VERSION 5.7 ;
  NOWIREEXTENSIONATPIN ON ;
  DIVIDERCHAR "/" ;
  BUSBITCHARS "[]" ;
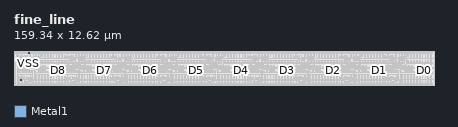
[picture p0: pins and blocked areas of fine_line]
MACRO fine_line
  CLASS BLOCK ;
  FOREIGN fine_line ;
  ORIGIN 0.430 0.430 ;
  SIZE 159.340 BY 12.620 ;
  PIN VSTART
    ANTENNAGATEAREA 0.396000 ;
    PORT
      LAYER Metal1 ;
        RECT 2.000 9.070 2.400 9.410 ;
    END
  END VSTART
  PIN VSTOP
    ANTENNAGATEAREA 0.396000 ;
    PORT
      LAYER Metal1 ;
        RECT 1.900 1.250 2.300 1.570 ;
    END
  END VSTOP
  PIN D8
    ANTENNADIFFAREA 0.897600 ;
    PORT
      LAYER Metal1 ;
        RECT 16.200 4.990 16.600 5.390 ;
    END
  END D8
  PIN D7
    ANTENNADIFFAREA 0.897600 ;
    PORT
      LAYER Metal1 ;
        RECT 33.560 4.990 33.960 5.390 ;
    END
  END D7
  PIN D6
    ANTENNADIFFAREA 0.897600 ;
    PORT
      LAYER Metal1 ;
        RECT 50.920 4.990 51.320 5.390 ;
    END
  END D6
  PIN D5
    ANTENNADIFFAREA 0.897600 ;
    PORT
      LAYER Metal1 ;
        RECT 68.280 4.990 68.680 5.390 ;
    END
  END D5
  PIN D4
    ANTENNADIFFAREA 0.897600 ;
    PORT
      LAYER Metal1 ;
        RECT 85.640 4.990 86.040 5.390 ;
    END
  END D4
  PIN D3
    ANTENNADIFFAREA 0.897600 ;
    PORT
      LAYER Metal1 ;
        RECT 103.000 4.990 103.400 5.390 ;
    END
  END D3
  PIN D2
    ANTENNADIFFAREA 0.897600 ;
    PORT
      LAYER Metal1 ;
        RECT 120.360 4.990 120.760 5.390 ;
    END
  END D2
  PIN D1
    ANTENNADIFFAREA 0.897600 ;
    PORT
      LAYER Metal1 ;
        RECT 137.720 4.990 138.120 5.390 ;
    END
  END D1
  PIN D0
    ANTENNADIFFAREA 0.897600 ;
    PORT
      LAYER Metal1 ;
        RECT 155.080 4.990 155.480 5.390 ;
    END
  END D0
  PIN VDD
    USE POWER ;
    PORT
      LAYER Metal1 ;
        RECT 5.000 11.610 5.400 11.910 ;
    END
  END VDD
  PIN VSS
    USE GROUND ;
    PORT
      LAYER Metal1 ;
        RECT 5.000 7.690 5.400 7.990 ;
    END
  END VSS
  OBS
      LAYER Nwell ;
        RECT -0.430 9.600 158.910 12.190 ;
      LAYER Pwell ;
        RECT -0.430 6.080 158.910 9.600 ;
      LAYER Nwell ;
        RECT -0.430 5.955 5.985 6.080 ;
      LAYER Pwell ;
        RECT 5.985 5.955 7.240 6.080 ;
      LAYER Nwell ;
        RECT 7.240 5.955 23.345 6.080 ;
      LAYER Pwell ;
        RECT 23.345 5.955 24.600 6.080 ;
      LAYER Nwell ;
        RECT 24.600 5.955 40.705 6.080 ;
      LAYER Pwell ;
        RECT 40.705 5.955 41.960 6.080 ;
      LAYER Nwell ;
        RECT 41.960 5.955 58.065 6.080 ;
      LAYER Pwell ;
        RECT 58.065 5.955 59.320 6.080 ;
      LAYER Nwell ;
        RECT 59.320 5.955 75.425 6.080 ;
      LAYER Pwell ;
        RECT 75.425 5.955 76.680 6.080 ;
      LAYER Nwell ;
        RECT 76.680 5.955 92.785 6.080 ;
      LAYER Pwell ;
        RECT 92.785 5.955 94.040 6.080 ;
      LAYER Nwell ;
        RECT 94.040 5.955 110.145 6.080 ;
      LAYER Pwell ;
        RECT 110.145 5.955 111.400 6.080 ;
      LAYER Nwell ;
        RECT 111.400 5.955 127.505 6.080 ;
      LAYER Pwell ;
        RECT 127.505 5.955 128.760 6.080 ;
      LAYER Nwell ;
        RECT 128.760 5.955 144.865 6.080 ;
      LAYER Pwell ;
        RECT 144.865 5.955 146.120 6.080 ;
      LAYER Nwell ;
        RECT 146.120 5.955 158.910 6.080 ;
        RECT -0.430 1.760 158.910 5.955 ;
      LAYER Pwell ;
        RECT -0.430 -0.430 158.910 1.760 ;
      LAYER Metal1 ;
        RECT 0.000 11.910 158.480 12.060 ;
        RECT 0.000 11.610 5.000 11.910 ;
        RECT 5.400 11.610 158.480 11.910 ;
        RECT 0.000 11.460 158.480 11.610 ;
        RECT 0.370 9.760 0.710 11.460 ;
        RECT 1.370 10.245 1.600 10.820 ;
        RECT 2.390 10.475 2.620 11.460 ;
        RECT 3.510 10.480 3.840 10.820 ;
        RECT 1.370 10.015 3.215 10.245 ;
        RECT 0.370 8.140 0.710 9.030 ;
        RECT 1.370 8.400 1.600 10.015 ;
        RECT 3.610 9.670 3.840 10.480 ;
        RECT 4.380 10.135 4.610 10.820 ;
        RECT 5.575 10.500 5.915 11.460 ;
        RECT 6.800 10.420 7.030 11.000 ;
        RECT 7.765 10.650 8.105 11.460 ;
        RECT 8.940 10.420 9.510 11.000 ;
        RECT 10.010 10.445 10.240 11.460 ;
        RECT 6.800 10.190 9.510 10.420 ;
        RECT 4.380 9.900 5.565 10.135 ;
        RECT 5.335 9.865 5.565 9.900 ;
        RECT 3.610 9.440 5.105 9.670 ;
        RECT 5.335 9.525 8.180 9.865 ;
        RECT 1.830 9.410 3.270 9.430 ;
        RECT 1.830 9.070 2.000 9.410 ;
        RECT 2.400 9.070 3.270 9.410 ;
        RECT 1.830 9.050 3.270 9.070 ;
        RECT 2.435 8.140 2.775 8.685 ;
        RECT 3.610 8.400 3.840 9.440 ;
        RECT 5.335 9.210 5.565 9.525 ;
        RECT 8.940 9.245 9.510 10.190 ;
        RECT 11.030 9.770 11.370 11.460 ;
        RECT 12.150 9.770 12.490 11.460 ;
        RECT 13.270 9.770 13.610 11.460 ;
        RECT 14.390 9.770 14.730 11.460 ;
        RECT 15.510 9.770 15.850 11.460 ;
        RECT 16.630 9.770 16.970 11.460 ;
        RECT 17.750 9.770 18.090 11.460 ;
        RECT 18.730 10.245 18.960 10.820 ;
        RECT 19.750 10.475 19.980 11.460 ;
        RECT 20.870 10.480 21.200 10.820 ;
        RECT 18.730 10.015 20.575 10.245 ;
        RECT 4.330 8.975 5.565 9.210 ;
        RECT 6.750 9.010 9.510 9.245 ;
        RECT 4.330 8.400 4.560 8.975 ;
        RECT 5.450 8.140 5.680 8.745 ;
        RECT 6.750 8.440 6.980 9.010 ;
        RECT 7.870 8.140 8.100 8.780 ;
        RECT 8.990 8.440 9.510 9.010 ;
        RECT 10.110 8.140 10.340 8.780 ;
        RECT 11.030 8.140 11.370 9.025 ;
        RECT 12.150 8.140 12.490 9.025 ;
        RECT 13.270 8.140 13.610 9.025 ;
        RECT 14.390 8.140 14.730 9.025 ;
        RECT 15.510 8.140 15.850 9.025 ;
        RECT 16.630 8.140 16.970 9.025 ;
        RECT 17.750 8.140 18.090 9.025 ;
        RECT 18.730 8.400 18.960 10.015 ;
        RECT 20.970 9.670 21.200 10.480 ;
        RECT 21.740 10.135 21.970 10.820 ;
        RECT 22.935 10.500 23.275 11.460 ;
        RECT 24.160 10.420 24.390 11.000 ;
        RECT 25.125 10.650 25.465 11.460 ;
        RECT 26.300 10.420 26.870 11.000 ;
        RECT 27.370 10.445 27.600 11.460 ;
        RECT 24.160 10.190 26.870 10.420 ;
        RECT 21.740 9.900 22.925 10.135 ;
        RECT 22.695 9.865 22.925 9.900 ;
        RECT 20.970 9.440 22.465 9.670 ;
        RECT 22.695 9.525 25.540 9.865 ;
        RECT 19.190 9.050 20.630 9.430 ;
        RECT 19.795 8.140 20.135 8.685 ;
        RECT 20.970 8.400 21.200 9.440 ;
        RECT 22.695 9.210 22.925 9.525 ;
        RECT 26.300 9.245 26.870 10.190 ;
        RECT 28.390 9.770 28.730 11.460 ;
        RECT 29.510 9.770 29.850 11.460 ;
        RECT 30.630 9.770 30.970 11.460 ;
        RECT 31.750 9.770 32.090 11.460 ;
        RECT 32.870 9.770 33.210 11.460 ;
        RECT 33.990 9.770 34.330 11.460 ;
        RECT 35.110 9.770 35.450 11.460 ;
        RECT 36.090 10.245 36.320 10.820 ;
        RECT 37.110 10.475 37.340 11.460 ;
        RECT 38.230 10.480 38.560 10.820 ;
        RECT 36.090 10.015 37.935 10.245 ;
        RECT 21.690 8.975 22.925 9.210 ;
        RECT 24.110 9.010 26.870 9.245 ;
        RECT 21.690 8.400 21.920 8.975 ;
        RECT 22.810 8.140 23.040 8.745 ;
        RECT 24.110 8.440 24.340 9.010 ;
        RECT 25.230 8.140 25.460 8.780 ;
        RECT 26.350 8.440 26.870 9.010 ;
        RECT 27.470 8.140 27.700 8.780 ;
        RECT 28.390 8.140 28.730 9.025 ;
        RECT 29.510 8.140 29.850 9.025 ;
        RECT 30.630 8.140 30.970 9.025 ;
        RECT 31.750 8.140 32.090 9.025 ;
        RECT 32.870 8.140 33.210 9.025 ;
        RECT 33.990 8.140 34.330 9.025 ;
        RECT 35.110 8.140 35.450 9.025 ;
        RECT 36.090 8.400 36.320 10.015 ;
        RECT 38.330 9.670 38.560 10.480 ;
        RECT 39.100 10.135 39.330 10.820 ;
        RECT 40.295 10.500 40.635 11.460 ;
        RECT 41.520 10.420 41.750 11.000 ;
        RECT 42.485 10.650 42.825 11.460 ;
        RECT 43.660 10.420 44.230 11.000 ;
        RECT 44.730 10.445 44.960 11.460 ;
        RECT 41.520 10.190 44.230 10.420 ;
        RECT 39.100 9.900 40.285 10.135 ;
        RECT 40.055 9.865 40.285 9.900 ;
        RECT 38.330 9.440 39.825 9.670 ;
        RECT 40.055 9.525 42.900 9.865 ;
        RECT 36.550 9.050 37.990 9.430 ;
        RECT 37.155 8.140 37.495 8.685 ;
        RECT 38.330 8.400 38.560 9.440 ;
        RECT 40.055 9.210 40.285 9.525 ;
        RECT 43.660 9.245 44.230 10.190 ;
        RECT 45.750 9.770 46.090 11.460 ;
        RECT 46.870 9.770 47.210 11.460 ;
        RECT 47.990 9.770 48.330 11.460 ;
        RECT 49.110 9.770 49.450 11.460 ;
        RECT 50.230 9.770 50.570 11.460 ;
        RECT 51.350 9.770 51.690 11.460 ;
        RECT 52.470 9.770 52.810 11.460 ;
        RECT 53.450 10.245 53.680 10.820 ;
        RECT 54.470 10.475 54.700 11.460 ;
        RECT 55.590 10.480 55.920 10.820 ;
        RECT 53.450 10.015 55.295 10.245 ;
        RECT 39.050 8.975 40.285 9.210 ;
        RECT 41.470 9.010 44.230 9.245 ;
        RECT 39.050 8.400 39.280 8.975 ;
        RECT 40.170 8.140 40.400 8.745 ;
        RECT 41.470 8.440 41.700 9.010 ;
        RECT 42.590 8.140 42.820 8.780 ;
        RECT 43.710 8.440 44.230 9.010 ;
        RECT 44.830 8.140 45.060 8.780 ;
        RECT 45.750 8.140 46.090 9.025 ;
        RECT 46.870 8.140 47.210 9.025 ;
        RECT 47.990 8.140 48.330 9.025 ;
        RECT 49.110 8.140 49.450 9.025 ;
        RECT 50.230 8.140 50.570 9.025 ;
        RECT 51.350 8.140 51.690 9.025 ;
        RECT 52.470 8.140 52.810 9.025 ;
        RECT 53.450 8.400 53.680 10.015 ;
        RECT 55.690 9.670 55.920 10.480 ;
        RECT 56.460 10.135 56.690 10.820 ;
        RECT 57.655 10.500 57.995 11.460 ;
        RECT 58.880 10.420 59.110 11.000 ;
        RECT 59.845 10.650 60.185 11.460 ;
        RECT 61.020 10.420 61.590 11.000 ;
        RECT 62.090 10.445 62.320 11.460 ;
        RECT 58.880 10.190 61.590 10.420 ;
        RECT 56.460 9.900 57.645 10.135 ;
        RECT 57.415 9.865 57.645 9.900 ;
        RECT 55.690 9.440 57.185 9.670 ;
        RECT 57.415 9.525 60.260 9.865 ;
        RECT 53.910 9.050 55.350 9.430 ;
        RECT 54.515 8.140 54.855 8.685 ;
        RECT 55.690 8.400 55.920 9.440 ;
        RECT 57.415 9.210 57.645 9.525 ;
        RECT 61.020 9.245 61.590 10.190 ;
        RECT 63.110 9.770 63.450 11.460 ;
        RECT 64.230 9.770 64.570 11.460 ;
        RECT 65.350 9.770 65.690 11.460 ;
        RECT 66.470 9.770 66.810 11.460 ;
        RECT 67.590 9.770 67.930 11.460 ;
        RECT 68.710 9.770 69.050 11.460 ;
        RECT 69.830 9.770 70.170 11.460 ;
        RECT 70.810 10.245 71.040 10.820 ;
        RECT 71.830 10.475 72.060 11.460 ;
        RECT 72.950 10.480 73.280 10.820 ;
        RECT 70.810 10.015 72.655 10.245 ;
        RECT 56.410 8.975 57.645 9.210 ;
        RECT 58.830 9.010 61.590 9.245 ;
        RECT 56.410 8.400 56.640 8.975 ;
        RECT 57.530 8.140 57.760 8.745 ;
        RECT 58.830 8.440 59.060 9.010 ;
        RECT 59.950 8.140 60.180 8.780 ;
        RECT 61.070 8.440 61.590 9.010 ;
        RECT 62.190 8.140 62.420 8.780 ;
        RECT 63.110 8.140 63.450 9.025 ;
        RECT 64.230 8.140 64.570 9.025 ;
        RECT 65.350 8.140 65.690 9.025 ;
        RECT 66.470 8.140 66.810 9.025 ;
        RECT 67.590 8.140 67.930 9.025 ;
        RECT 68.710 8.140 69.050 9.025 ;
        RECT 69.830 8.140 70.170 9.025 ;
        RECT 70.810 8.400 71.040 10.015 ;
        RECT 73.050 9.670 73.280 10.480 ;
        RECT 73.820 10.135 74.050 10.820 ;
        RECT 75.015 10.500 75.355 11.460 ;
        RECT 76.240 10.420 76.470 11.000 ;
        RECT 77.205 10.650 77.545 11.460 ;
        RECT 78.380 10.420 78.950 11.000 ;
        RECT 79.450 10.445 79.680 11.460 ;
        RECT 76.240 10.190 78.950 10.420 ;
        RECT 73.820 9.900 75.005 10.135 ;
        RECT 74.775 9.865 75.005 9.900 ;
        RECT 73.050 9.440 74.545 9.670 ;
        RECT 74.775 9.525 77.620 9.865 ;
        RECT 71.270 9.050 72.710 9.430 ;
        RECT 71.875 8.140 72.215 8.685 ;
        RECT 73.050 8.400 73.280 9.440 ;
        RECT 74.775 9.210 75.005 9.525 ;
        RECT 78.380 9.245 78.950 10.190 ;
        RECT 80.470 9.770 80.810 11.460 ;
        RECT 81.590 9.770 81.930 11.460 ;
        RECT 82.710 9.770 83.050 11.460 ;
        RECT 83.830 9.770 84.170 11.460 ;
        RECT 84.950 9.770 85.290 11.460 ;
        RECT 86.070 9.770 86.410 11.460 ;
        RECT 87.190 9.770 87.530 11.460 ;
        RECT 88.170 10.245 88.400 10.820 ;
        RECT 89.190 10.475 89.420 11.460 ;
        RECT 90.310 10.480 90.640 10.820 ;
        RECT 88.170 10.015 90.015 10.245 ;
        RECT 73.770 8.975 75.005 9.210 ;
        RECT 76.190 9.010 78.950 9.245 ;
        RECT 73.770 8.400 74.000 8.975 ;
        RECT 74.890 8.140 75.120 8.745 ;
        RECT 76.190 8.440 76.420 9.010 ;
        RECT 77.310 8.140 77.540 8.780 ;
        RECT 78.430 8.440 78.950 9.010 ;
        RECT 79.550 8.140 79.780 8.780 ;
        RECT 80.470 8.140 80.810 9.025 ;
        RECT 81.590 8.140 81.930 9.025 ;
        RECT 82.710 8.140 83.050 9.025 ;
        RECT 83.830 8.140 84.170 9.025 ;
        RECT 84.950 8.140 85.290 9.025 ;
        RECT 86.070 8.140 86.410 9.025 ;
        RECT 87.190 8.140 87.530 9.025 ;
        RECT 88.170 8.400 88.400 10.015 ;
        RECT 90.410 9.670 90.640 10.480 ;
        RECT 91.180 10.135 91.410 10.820 ;
        RECT 92.375 10.500 92.715 11.460 ;
        RECT 93.600 10.420 93.830 11.000 ;
        RECT 94.565 10.650 94.905 11.460 ;
        RECT 95.740 10.420 96.310 11.000 ;
        RECT 96.810 10.445 97.040 11.460 ;
        RECT 93.600 10.190 96.310 10.420 ;
        RECT 91.180 9.900 92.365 10.135 ;
        RECT 92.135 9.865 92.365 9.900 ;
        RECT 90.410 9.440 91.905 9.670 ;
        RECT 92.135 9.525 94.980 9.865 ;
        RECT 88.630 9.050 90.070 9.430 ;
        RECT 89.235 8.140 89.575 8.685 ;
        RECT 90.410 8.400 90.640 9.440 ;
        RECT 92.135 9.210 92.365 9.525 ;
        RECT 95.740 9.245 96.310 10.190 ;
        RECT 97.830 9.770 98.170 11.460 ;
        RECT 98.950 9.770 99.290 11.460 ;
        RECT 100.070 9.770 100.410 11.460 ;
        RECT 101.190 9.770 101.530 11.460 ;
        RECT 102.310 9.770 102.650 11.460 ;
        RECT 103.430 9.770 103.770 11.460 ;
        RECT 104.550 9.770 104.890 11.460 ;
        RECT 105.530 10.245 105.760 10.820 ;
        RECT 106.550 10.475 106.780 11.460 ;
        RECT 107.670 10.480 108.000 10.820 ;
        RECT 105.530 10.015 107.375 10.245 ;
        RECT 91.130 8.975 92.365 9.210 ;
        RECT 93.550 9.010 96.310 9.245 ;
        RECT 91.130 8.400 91.360 8.975 ;
        RECT 92.250 8.140 92.480 8.745 ;
        RECT 93.550 8.440 93.780 9.010 ;
        RECT 94.670 8.140 94.900 8.780 ;
        RECT 95.790 8.440 96.310 9.010 ;
        RECT 96.910 8.140 97.140 8.780 ;
        RECT 97.830 8.140 98.170 9.025 ;
        RECT 98.950 8.140 99.290 9.025 ;
        RECT 100.070 8.140 100.410 9.025 ;
        RECT 101.190 8.140 101.530 9.025 ;
        RECT 102.310 8.140 102.650 9.025 ;
        RECT 103.430 8.140 103.770 9.025 ;
        RECT 104.550 8.140 104.890 9.025 ;
        RECT 105.530 8.400 105.760 10.015 ;
        RECT 107.770 9.670 108.000 10.480 ;
        RECT 108.540 10.135 108.770 10.820 ;
        RECT 109.735 10.500 110.075 11.460 ;
        RECT 110.960 10.420 111.190 11.000 ;
        RECT 111.925 10.650 112.265 11.460 ;
        RECT 113.100 10.420 113.670 11.000 ;
        RECT 114.170 10.445 114.400 11.460 ;
        RECT 110.960 10.190 113.670 10.420 ;
        RECT 108.540 9.900 109.725 10.135 ;
        RECT 109.495 9.865 109.725 9.900 ;
        RECT 107.770 9.440 109.265 9.670 ;
        RECT 109.495 9.525 112.340 9.865 ;
        RECT 105.990 9.050 107.430 9.430 ;
        RECT 106.595 8.140 106.935 8.685 ;
        RECT 107.770 8.400 108.000 9.440 ;
        RECT 109.495 9.210 109.725 9.525 ;
        RECT 113.100 9.245 113.670 10.190 ;
        RECT 115.190 9.770 115.530 11.460 ;
        RECT 116.310 9.770 116.650 11.460 ;
        RECT 117.430 9.770 117.770 11.460 ;
        RECT 118.550 9.770 118.890 11.460 ;
        RECT 119.670 9.770 120.010 11.460 ;
        RECT 120.790 9.770 121.130 11.460 ;
        RECT 121.910 9.770 122.250 11.460 ;
        RECT 122.890 10.245 123.120 10.820 ;
        RECT 123.910 10.475 124.140 11.460 ;
        RECT 125.030 10.480 125.360 10.820 ;
        RECT 122.890 10.015 124.735 10.245 ;
        RECT 108.490 8.975 109.725 9.210 ;
        RECT 110.910 9.010 113.670 9.245 ;
        RECT 108.490 8.400 108.720 8.975 ;
        RECT 109.610 8.140 109.840 8.745 ;
        RECT 110.910 8.440 111.140 9.010 ;
        RECT 112.030 8.140 112.260 8.780 ;
        RECT 113.150 8.440 113.670 9.010 ;
        RECT 114.270 8.140 114.500 8.780 ;
        RECT 115.190 8.140 115.530 9.025 ;
        RECT 116.310 8.140 116.650 9.025 ;
        RECT 117.430 8.140 117.770 9.025 ;
        RECT 118.550 8.140 118.890 9.025 ;
        RECT 119.670 8.140 120.010 9.025 ;
        RECT 120.790 8.140 121.130 9.025 ;
        RECT 121.910 8.140 122.250 9.025 ;
        RECT 122.890 8.400 123.120 10.015 ;
        RECT 125.130 9.670 125.360 10.480 ;
        RECT 125.900 10.135 126.130 10.820 ;
        RECT 127.095 10.500 127.435 11.460 ;
        RECT 128.320 10.420 128.550 11.000 ;
        RECT 129.285 10.650 129.625 11.460 ;
        RECT 130.460 10.420 131.030 11.000 ;
        RECT 131.530 10.445 131.760 11.460 ;
        RECT 128.320 10.190 131.030 10.420 ;
        RECT 125.900 9.900 127.085 10.135 ;
        RECT 126.855 9.865 127.085 9.900 ;
        RECT 125.130 9.440 126.625 9.670 ;
        RECT 126.855 9.525 129.700 9.865 ;
        RECT 123.350 9.050 124.790 9.430 ;
        RECT 123.955 8.140 124.295 8.685 ;
        RECT 125.130 8.400 125.360 9.440 ;
        RECT 126.855 9.210 127.085 9.525 ;
        RECT 130.460 9.245 131.030 10.190 ;
        RECT 132.550 9.770 132.890 11.460 ;
        RECT 133.670 9.770 134.010 11.460 ;
        RECT 134.790 9.770 135.130 11.460 ;
        RECT 135.910 9.770 136.250 11.460 ;
        RECT 137.030 9.770 137.370 11.460 ;
        RECT 138.150 9.770 138.490 11.460 ;
        RECT 139.270 9.770 139.610 11.460 ;
        RECT 140.250 10.245 140.480 10.820 ;
        RECT 141.270 10.475 141.500 11.460 ;
        RECT 142.390 10.480 142.720 10.820 ;
        RECT 140.250 10.015 142.095 10.245 ;
        RECT 125.850 8.975 127.085 9.210 ;
        RECT 128.270 9.010 131.030 9.245 ;
        RECT 125.850 8.400 126.080 8.975 ;
        RECT 126.970 8.140 127.200 8.745 ;
        RECT 128.270 8.440 128.500 9.010 ;
        RECT 129.390 8.140 129.620 8.780 ;
        RECT 130.510 8.440 131.030 9.010 ;
        RECT 131.630 8.140 131.860 8.780 ;
        RECT 132.550 8.140 132.890 9.025 ;
        RECT 133.670 8.140 134.010 9.025 ;
        RECT 134.790 8.140 135.130 9.025 ;
        RECT 135.910 8.140 136.250 9.025 ;
        RECT 137.030 8.140 137.370 9.025 ;
        RECT 138.150 8.140 138.490 9.025 ;
        RECT 139.270 8.140 139.610 9.025 ;
        RECT 140.250 8.400 140.480 10.015 ;
        RECT 142.490 9.670 142.720 10.480 ;
        RECT 143.260 10.135 143.490 10.820 ;
        RECT 144.455 10.500 144.795 11.460 ;
        RECT 145.680 10.420 145.910 11.000 ;
        RECT 146.645 10.650 146.985 11.460 ;
        RECT 147.820 10.420 148.390 11.000 ;
        RECT 148.890 10.445 149.120 11.460 ;
        RECT 145.680 10.190 148.390 10.420 ;
        RECT 143.260 9.900 144.445 10.135 ;
        RECT 144.215 9.865 144.445 9.900 ;
        RECT 142.490 9.440 143.985 9.670 ;
        RECT 144.215 9.525 147.060 9.865 ;
        RECT 140.710 9.050 142.150 9.430 ;
        RECT 141.315 8.140 141.655 8.685 ;
        RECT 142.490 8.400 142.720 9.440 ;
        RECT 144.215 9.210 144.445 9.525 ;
        RECT 147.820 9.245 148.390 10.190 ;
        RECT 149.910 9.770 150.250 11.460 ;
        RECT 151.030 9.770 151.370 11.460 ;
        RECT 152.150 9.770 152.490 11.460 ;
        RECT 153.270 9.770 153.610 11.460 ;
        RECT 154.390 9.770 154.730 11.460 ;
        RECT 155.510 9.770 155.850 11.460 ;
        RECT 156.630 9.770 156.970 11.460 ;
        RECT 157.730 9.760 158.070 11.460 ;
        RECT 143.210 8.975 144.445 9.210 ;
        RECT 145.630 9.010 148.390 9.245 ;
        RECT 143.210 8.400 143.440 8.975 ;
        RECT 144.330 8.140 144.560 8.745 ;
        RECT 145.630 8.440 145.860 9.010 ;
        RECT 146.750 8.140 146.980 8.780 ;
        RECT 147.870 8.440 148.390 9.010 ;
        RECT 148.990 8.140 149.220 8.780 ;
        RECT 149.910 8.140 150.250 9.025 ;
        RECT 151.030 8.140 151.370 9.025 ;
        RECT 152.150 8.140 152.490 9.025 ;
        RECT 153.270 8.140 153.610 9.025 ;
        RECT 154.390 8.140 154.730 9.025 ;
        RECT 155.510 8.140 155.850 9.025 ;
        RECT 156.630 8.140 156.970 9.025 ;
        RECT 157.730 8.140 158.070 9.030 ;
        RECT 0.000 7.990 158.480 8.140 ;
        RECT 0.000 7.690 5.000 7.990 ;
        RECT 5.400 7.690 158.480 7.990 ;
        RECT 0.000 7.540 158.480 7.690 ;
        RECT 0.370 6.650 0.710 7.540 ;
        RECT 1.365 6.560 1.595 7.030 ;
        RECT 2.430 6.790 2.770 7.540 ;
        RECT 1.365 6.330 3.265 6.560 ;
        RECT 0.370 4.220 0.710 5.920 ;
        RECT 1.770 5.690 2.710 6.070 ;
        RECT 3.035 5.370 3.265 6.330 ;
        RECT 3.605 6.515 3.835 7.030 ;
        RECT 4.270 6.750 4.610 7.540 ;
        RECT 4.965 7.080 7.515 7.310 ;
        RECT 8.910 7.255 9.250 7.540 ;
        RECT 4.965 6.515 5.195 7.080 ;
        RECT 3.605 6.285 5.195 6.515 ;
        RECT 4.965 5.750 5.195 6.285 ;
        RECT 1.465 5.140 3.265 5.370 ;
        RECT 1.465 4.685 1.695 5.140 ;
        RECT 2.430 4.220 2.770 4.910 ;
        RECT 3.035 4.860 3.265 5.140 ;
        RECT 3.505 5.515 5.195 5.750 ;
        RECT 3.505 5.130 3.735 5.515 ;
        RECT 3.965 4.955 5.240 5.190 ;
        RECT 5.690 5.130 6.095 6.630 ;
        RECT 6.445 5.600 6.790 6.850 ;
        RECT 7.285 6.060 7.515 7.080 ;
        RECT 10.250 6.520 10.590 6.980 ;
        RECT 8.250 6.290 10.590 6.520 ;
        RECT 7.285 5.830 9.990 6.060 ;
        RECT 6.445 5.370 9.530 5.600 ;
        RECT 3.965 4.860 4.195 4.955 ;
        RECT 3.035 4.625 4.195 4.860 ;
        RECT 5.010 4.680 5.240 4.955 ;
        RECT 6.730 4.910 7.070 5.370 ;
        RECT 4.425 4.220 4.655 4.655 ;
        RECT 5.010 4.450 7.710 4.680 ;
        RECT 8.750 4.220 9.090 5.140 ;
        RECT 9.760 4.680 9.990 5.830 ;
        RECT 10.245 4.910 10.590 6.290 ;
        RECT 10.840 4.680 11.070 6.615 ;
        RECT 11.370 5.945 11.710 6.980 ;
        RECT 13.605 6.735 13.835 7.540 ;
        RECT 14.725 6.440 14.990 7.085 ;
        RECT 15.545 6.950 15.775 7.540 ;
        RECT 12.890 6.340 14.990 6.440 ;
        RECT 12.890 6.210 16.215 6.340 ;
        RECT 14.765 6.000 16.215 6.210 ;
        RECT 11.370 5.710 14.470 5.945 ;
        RECT 11.370 4.910 11.710 5.710 ;
        RECT 9.760 4.450 12.450 4.680 ;
        RECT 13.745 4.220 13.975 5.205 ;
        RECT 14.765 4.810 14.995 6.000 ;
        RECT 16.590 5.510 16.970 7.290 ;
        RECT 17.750 6.655 18.090 7.540 ;
        RECT 18.725 6.560 18.955 7.030 ;
        RECT 19.790 6.790 20.130 7.540 ;
        RECT 18.725 6.330 20.625 6.560 ;
        RECT 15.955 5.390 16.970 5.510 ;
        RECT 15.485 4.220 15.715 5.205 ;
        RECT 15.955 4.990 16.200 5.390 ;
        RECT 16.600 4.990 16.970 5.390 ;
        RECT 15.955 4.865 16.970 4.990 ;
        RECT 17.750 4.220 18.090 5.910 ;
        RECT 19.130 5.690 20.070 6.070 ;
        RECT 20.395 5.370 20.625 6.330 ;
        RECT 20.965 6.515 21.195 7.030 ;
        RECT 21.630 6.750 21.970 7.540 ;
        RECT 22.325 7.080 24.875 7.310 ;
        RECT 26.270 7.255 26.610 7.540 ;
        RECT 22.325 6.515 22.555 7.080 ;
        RECT 20.965 6.285 22.555 6.515 ;
        RECT 22.325 5.750 22.555 6.285 ;
        RECT 18.825 5.140 20.625 5.370 ;
        RECT 18.825 4.685 19.055 5.140 ;
        RECT 19.790 4.220 20.130 4.910 ;
        RECT 20.395 4.860 20.625 5.140 ;
        RECT 20.865 5.515 22.555 5.750 ;
        RECT 20.865 5.130 21.095 5.515 ;
        RECT 21.325 4.955 22.600 5.190 ;
        RECT 23.050 5.130 23.455 6.630 ;
        RECT 23.805 5.600 24.150 6.850 ;
        RECT 24.645 6.060 24.875 7.080 ;
        RECT 27.610 6.520 27.950 6.980 ;
        RECT 25.610 6.290 27.950 6.520 ;
        RECT 24.645 5.830 27.350 6.060 ;
        RECT 23.805 5.370 26.890 5.600 ;
        RECT 21.325 4.860 21.555 4.955 ;
        RECT 20.395 4.625 21.555 4.860 ;
        RECT 22.370 4.680 22.600 4.955 ;
        RECT 24.090 4.910 24.430 5.370 ;
        RECT 21.785 4.220 22.015 4.655 ;
        RECT 22.370 4.450 25.070 4.680 ;
        RECT 26.110 4.220 26.450 5.140 ;
        RECT 27.120 4.680 27.350 5.830 ;
        RECT 27.605 4.910 27.950 6.290 ;
        RECT 28.200 4.680 28.430 6.615 ;
        RECT 28.730 5.945 29.070 6.980 ;
        RECT 30.965 6.735 31.195 7.540 ;
        RECT 32.085 6.440 32.350 7.085 ;
        RECT 32.905 6.950 33.135 7.540 ;
        RECT 30.250 6.340 32.350 6.440 ;
        RECT 30.250 6.210 33.575 6.340 ;
        RECT 32.125 6.000 33.575 6.210 ;
        RECT 28.730 5.710 31.830 5.945 ;
        RECT 28.730 4.910 29.070 5.710 ;
        RECT 27.120 4.450 29.810 4.680 ;
        RECT 31.105 4.220 31.335 5.205 ;
        RECT 32.125 4.810 32.355 6.000 ;
        RECT 33.950 5.510 34.330 7.290 ;
        RECT 35.110 6.655 35.450 7.540 ;
        RECT 36.085 6.560 36.315 7.030 ;
        RECT 37.150 6.790 37.490 7.540 ;
        RECT 36.085 6.330 37.985 6.560 ;
        RECT 33.315 5.390 34.330 5.510 ;
        RECT 32.845 4.220 33.075 5.205 ;
        RECT 33.315 4.990 33.560 5.390 ;
        RECT 33.960 4.990 34.330 5.390 ;
        RECT 33.315 4.865 34.330 4.990 ;
        RECT 35.110 4.220 35.450 5.910 ;
        RECT 36.490 5.690 37.430 6.070 ;
        RECT 37.755 5.370 37.985 6.330 ;
        RECT 38.325 6.515 38.555 7.030 ;
        RECT 38.990 6.750 39.330 7.540 ;
        RECT 39.685 7.080 42.235 7.310 ;
        RECT 43.630 7.255 43.970 7.540 ;
        RECT 39.685 6.515 39.915 7.080 ;
        RECT 38.325 6.285 39.915 6.515 ;
        RECT 39.685 5.750 39.915 6.285 ;
        RECT 36.185 5.140 37.985 5.370 ;
        RECT 36.185 4.685 36.415 5.140 ;
        RECT 37.150 4.220 37.490 4.910 ;
        RECT 37.755 4.860 37.985 5.140 ;
        RECT 38.225 5.515 39.915 5.750 ;
        RECT 38.225 5.130 38.455 5.515 ;
        RECT 38.685 4.955 39.960 5.190 ;
        RECT 40.410 5.130 40.815 6.630 ;
        RECT 41.165 5.600 41.510 6.850 ;
        RECT 42.005 6.060 42.235 7.080 ;
        RECT 44.970 6.520 45.310 6.980 ;
        RECT 42.970 6.290 45.310 6.520 ;
        RECT 42.005 5.830 44.710 6.060 ;
        RECT 41.165 5.370 44.250 5.600 ;
        RECT 38.685 4.860 38.915 4.955 ;
        RECT 37.755 4.625 38.915 4.860 ;
        RECT 39.730 4.680 39.960 4.955 ;
        RECT 41.450 4.910 41.790 5.370 ;
        RECT 39.145 4.220 39.375 4.655 ;
        RECT 39.730 4.450 42.430 4.680 ;
        RECT 43.470 4.220 43.810 5.140 ;
        RECT 44.480 4.680 44.710 5.830 ;
        RECT 44.965 4.910 45.310 6.290 ;
        RECT 45.560 4.680 45.790 6.615 ;
        RECT 46.090 5.945 46.430 6.980 ;
        RECT 48.325 6.735 48.555 7.540 ;
        RECT 49.445 6.440 49.710 7.085 ;
        RECT 50.265 6.950 50.495 7.540 ;
        RECT 47.610 6.340 49.710 6.440 ;
        RECT 47.610 6.210 50.935 6.340 ;
        RECT 49.485 6.000 50.935 6.210 ;
        RECT 46.090 5.710 49.190 5.945 ;
        RECT 46.090 4.910 46.430 5.710 ;
        RECT 44.480 4.450 47.170 4.680 ;
        RECT 48.465 4.220 48.695 5.205 ;
        RECT 49.485 4.810 49.715 6.000 ;
        RECT 51.310 5.510 51.690 7.290 ;
        RECT 52.470 6.655 52.810 7.540 ;
        RECT 53.445 6.560 53.675 7.030 ;
        RECT 54.510 6.790 54.850 7.540 ;
        RECT 53.445 6.330 55.345 6.560 ;
        RECT 50.675 5.390 51.690 5.510 ;
        RECT 50.205 4.220 50.435 5.205 ;
        RECT 50.675 4.990 50.920 5.390 ;
        RECT 51.320 4.990 51.690 5.390 ;
        RECT 50.675 4.865 51.690 4.990 ;
        RECT 52.470 4.220 52.810 5.910 ;
        RECT 53.850 5.690 54.790 6.070 ;
        RECT 55.115 5.370 55.345 6.330 ;
        RECT 55.685 6.515 55.915 7.030 ;
        RECT 56.350 6.750 56.690 7.540 ;
        RECT 57.045 7.080 59.595 7.310 ;
        RECT 60.990 7.255 61.330 7.540 ;
        RECT 57.045 6.515 57.275 7.080 ;
        RECT 55.685 6.285 57.275 6.515 ;
        RECT 57.045 5.750 57.275 6.285 ;
        RECT 53.545 5.140 55.345 5.370 ;
        RECT 53.545 4.685 53.775 5.140 ;
        RECT 54.510 4.220 54.850 4.910 ;
        RECT 55.115 4.860 55.345 5.140 ;
        RECT 55.585 5.515 57.275 5.750 ;
        RECT 55.585 5.130 55.815 5.515 ;
        RECT 56.045 4.955 57.320 5.190 ;
        RECT 57.770 5.130 58.175 6.630 ;
        RECT 58.525 5.600 58.870 6.850 ;
        RECT 59.365 6.060 59.595 7.080 ;
        RECT 62.330 6.520 62.670 6.980 ;
        RECT 60.330 6.290 62.670 6.520 ;
        RECT 59.365 5.830 62.070 6.060 ;
        RECT 58.525 5.370 61.610 5.600 ;
        RECT 56.045 4.860 56.275 4.955 ;
        RECT 55.115 4.625 56.275 4.860 ;
        RECT 57.090 4.680 57.320 4.955 ;
        RECT 58.810 4.910 59.150 5.370 ;
        RECT 56.505 4.220 56.735 4.655 ;
        RECT 57.090 4.450 59.790 4.680 ;
        RECT 60.830 4.220 61.170 5.140 ;
        RECT 61.840 4.680 62.070 5.830 ;
        RECT 62.325 4.910 62.670 6.290 ;
        RECT 62.920 4.680 63.150 6.615 ;
        RECT 63.450 5.945 63.790 6.980 ;
        RECT 65.685 6.735 65.915 7.540 ;
        RECT 66.805 6.440 67.070 7.085 ;
        RECT 67.625 6.950 67.855 7.540 ;
        RECT 64.970 6.340 67.070 6.440 ;
        RECT 64.970 6.210 68.295 6.340 ;
        RECT 66.845 6.000 68.295 6.210 ;
        RECT 63.450 5.710 66.550 5.945 ;
        RECT 63.450 4.910 63.790 5.710 ;
        RECT 61.840 4.450 64.530 4.680 ;
        RECT 65.825 4.220 66.055 5.205 ;
        RECT 66.845 4.810 67.075 6.000 ;
        RECT 68.670 5.510 69.050 7.290 ;
        RECT 69.830 6.655 70.170 7.540 ;
        RECT 70.805 6.560 71.035 7.030 ;
        RECT 71.870 6.790 72.210 7.540 ;
        RECT 70.805 6.330 72.705 6.560 ;
        RECT 68.035 5.390 69.050 5.510 ;
        RECT 67.565 4.220 67.795 5.205 ;
        RECT 68.035 4.990 68.280 5.390 ;
        RECT 68.680 4.990 69.050 5.390 ;
        RECT 68.035 4.865 69.050 4.990 ;
        RECT 69.830 4.220 70.170 5.910 ;
        RECT 71.210 5.690 72.150 6.070 ;
        RECT 72.475 5.370 72.705 6.330 ;
        RECT 73.045 6.515 73.275 7.030 ;
        RECT 73.710 6.750 74.050 7.540 ;
        RECT 74.405 7.080 76.955 7.310 ;
        RECT 78.350 7.255 78.690 7.540 ;
        RECT 74.405 6.515 74.635 7.080 ;
        RECT 73.045 6.285 74.635 6.515 ;
        RECT 74.405 5.750 74.635 6.285 ;
        RECT 70.905 5.140 72.705 5.370 ;
        RECT 70.905 4.685 71.135 5.140 ;
        RECT 71.870 4.220 72.210 4.910 ;
        RECT 72.475 4.860 72.705 5.140 ;
        RECT 72.945 5.515 74.635 5.750 ;
        RECT 72.945 5.130 73.175 5.515 ;
        RECT 73.405 4.955 74.680 5.190 ;
        RECT 75.130 5.130 75.535 6.630 ;
        RECT 75.885 5.600 76.230 6.850 ;
        RECT 76.725 6.060 76.955 7.080 ;
        RECT 79.690 6.520 80.030 6.980 ;
        RECT 77.690 6.290 80.030 6.520 ;
        RECT 76.725 5.830 79.430 6.060 ;
        RECT 75.885 5.370 78.970 5.600 ;
        RECT 73.405 4.860 73.635 4.955 ;
        RECT 72.475 4.625 73.635 4.860 ;
        RECT 74.450 4.680 74.680 4.955 ;
        RECT 76.170 4.910 76.510 5.370 ;
        RECT 73.865 4.220 74.095 4.655 ;
        RECT 74.450 4.450 77.150 4.680 ;
        RECT 78.190 4.220 78.530 5.140 ;
        RECT 79.200 4.680 79.430 5.830 ;
        RECT 79.685 4.910 80.030 6.290 ;
        RECT 80.280 4.680 80.510 6.615 ;
        RECT 80.810 5.945 81.150 6.980 ;
        RECT 83.045 6.735 83.275 7.540 ;
        RECT 84.165 6.440 84.430 7.085 ;
        RECT 84.985 6.950 85.215 7.540 ;
        RECT 82.330 6.340 84.430 6.440 ;
        RECT 82.330 6.210 85.655 6.340 ;
        RECT 84.205 6.000 85.655 6.210 ;
        RECT 80.810 5.710 83.910 5.945 ;
        RECT 80.810 4.910 81.150 5.710 ;
        RECT 79.200 4.450 81.890 4.680 ;
        RECT 83.185 4.220 83.415 5.205 ;
        RECT 84.205 4.810 84.435 6.000 ;
        RECT 86.030 5.510 86.410 7.290 ;
        RECT 87.190 6.655 87.530 7.540 ;
        RECT 88.165 6.560 88.395 7.030 ;
        RECT 89.230 6.790 89.570 7.540 ;
        RECT 88.165 6.330 90.065 6.560 ;
        RECT 85.395 5.390 86.410 5.510 ;
        RECT 84.925 4.220 85.155 5.205 ;
        RECT 85.395 4.990 85.640 5.390 ;
        RECT 86.040 4.990 86.410 5.390 ;
        RECT 85.395 4.865 86.410 4.990 ;
        RECT 87.190 4.220 87.530 5.910 ;
        RECT 88.570 5.690 89.510 6.070 ;
        RECT 89.835 5.370 90.065 6.330 ;
        RECT 90.405 6.515 90.635 7.030 ;
        RECT 91.070 6.750 91.410 7.540 ;
        RECT 91.765 7.080 94.315 7.310 ;
        RECT 95.710 7.255 96.050 7.540 ;
        RECT 91.765 6.515 91.995 7.080 ;
        RECT 90.405 6.285 91.995 6.515 ;
        RECT 91.765 5.750 91.995 6.285 ;
        RECT 88.265 5.140 90.065 5.370 ;
        RECT 88.265 4.685 88.495 5.140 ;
        RECT 89.230 4.220 89.570 4.910 ;
        RECT 89.835 4.860 90.065 5.140 ;
        RECT 90.305 5.515 91.995 5.750 ;
        RECT 90.305 5.130 90.535 5.515 ;
        RECT 90.765 4.955 92.040 5.190 ;
        RECT 92.490 5.130 92.895 6.630 ;
        RECT 93.245 5.600 93.590 6.850 ;
        RECT 94.085 6.060 94.315 7.080 ;
        RECT 97.050 6.520 97.390 6.980 ;
        RECT 95.050 6.290 97.390 6.520 ;
        RECT 94.085 5.830 96.790 6.060 ;
        RECT 93.245 5.370 96.330 5.600 ;
        RECT 90.765 4.860 90.995 4.955 ;
        RECT 89.835 4.625 90.995 4.860 ;
        RECT 91.810 4.680 92.040 4.955 ;
        RECT 93.530 4.910 93.870 5.370 ;
        RECT 91.225 4.220 91.455 4.655 ;
        RECT 91.810 4.450 94.510 4.680 ;
        RECT 95.550 4.220 95.890 5.140 ;
        RECT 96.560 4.680 96.790 5.830 ;
        RECT 97.045 4.910 97.390 6.290 ;
        RECT 97.640 4.680 97.870 6.615 ;
        RECT 98.170 5.945 98.510 6.980 ;
        RECT 100.405 6.735 100.635 7.540 ;
        RECT 101.525 6.440 101.790 7.085 ;
        RECT 102.345 6.950 102.575 7.540 ;
        RECT 99.690 6.340 101.790 6.440 ;
        RECT 99.690 6.210 103.015 6.340 ;
        RECT 101.565 6.000 103.015 6.210 ;
        RECT 98.170 5.710 101.270 5.945 ;
        RECT 98.170 4.910 98.510 5.710 ;
        RECT 96.560 4.450 99.250 4.680 ;
        RECT 100.545 4.220 100.775 5.205 ;
        RECT 101.565 4.810 101.795 6.000 ;
        RECT 103.390 5.510 103.770 7.290 ;
        RECT 104.550 6.655 104.890 7.540 ;
        RECT 105.525 6.560 105.755 7.030 ;
        RECT 106.590 6.790 106.930 7.540 ;
        RECT 105.525 6.330 107.425 6.560 ;
        RECT 102.755 5.390 103.770 5.510 ;
        RECT 102.285 4.220 102.515 5.205 ;
        RECT 102.755 4.990 103.000 5.390 ;
        RECT 103.400 4.990 103.770 5.390 ;
        RECT 102.755 4.865 103.770 4.990 ;
        RECT 104.550 4.220 104.890 5.910 ;
        RECT 105.930 5.690 106.870 6.070 ;
        RECT 107.195 5.370 107.425 6.330 ;
        RECT 107.765 6.515 107.995 7.030 ;
        RECT 108.430 6.750 108.770 7.540 ;
        RECT 109.125 7.080 111.675 7.310 ;
        RECT 113.070 7.255 113.410 7.540 ;
        RECT 109.125 6.515 109.355 7.080 ;
        RECT 107.765 6.285 109.355 6.515 ;
        RECT 109.125 5.750 109.355 6.285 ;
        RECT 105.625 5.140 107.425 5.370 ;
        RECT 105.625 4.685 105.855 5.140 ;
        RECT 106.590 4.220 106.930 4.910 ;
        RECT 107.195 4.860 107.425 5.140 ;
        RECT 107.665 5.515 109.355 5.750 ;
        RECT 107.665 5.130 107.895 5.515 ;
        RECT 108.125 4.955 109.400 5.190 ;
        RECT 109.850 5.130 110.255 6.630 ;
        RECT 110.605 5.600 110.950 6.850 ;
        RECT 111.445 6.060 111.675 7.080 ;
        RECT 114.410 6.520 114.750 6.980 ;
        RECT 112.410 6.290 114.750 6.520 ;
        RECT 111.445 5.830 114.150 6.060 ;
        RECT 110.605 5.370 113.690 5.600 ;
        RECT 108.125 4.860 108.355 4.955 ;
        RECT 107.195 4.625 108.355 4.860 ;
        RECT 109.170 4.680 109.400 4.955 ;
        RECT 110.890 4.910 111.230 5.370 ;
        RECT 108.585 4.220 108.815 4.655 ;
        RECT 109.170 4.450 111.870 4.680 ;
        RECT 112.910 4.220 113.250 5.140 ;
        RECT 113.920 4.680 114.150 5.830 ;
        RECT 114.405 4.910 114.750 6.290 ;
        RECT 115.000 4.680 115.230 6.615 ;
        RECT 115.530 5.945 115.870 6.980 ;
        RECT 117.765 6.735 117.995 7.540 ;
        RECT 118.885 6.440 119.150 7.085 ;
        RECT 119.705 6.950 119.935 7.540 ;
        RECT 117.050 6.340 119.150 6.440 ;
        RECT 117.050 6.210 120.375 6.340 ;
        RECT 118.925 6.000 120.375 6.210 ;
        RECT 115.530 5.710 118.630 5.945 ;
        RECT 115.530 4.910 115.870 5.710 ;
        RECT 113.920 4.450 116.610 4.680 ;
        RECT 117.905 4.220 118.135 5.205 ;
        RECT 118.925 4.810 119.155 6.000 ;
        RECT 120.750 5.510 121.130 7.290 ;
        RECT 121.910 6.655 122.250 7.540 ;
        RECT 122.885 6.560 123.115 7.030 ;
        RECT 123.950 6.790 124.290 7.540 ;
        RECT 122.885 6.330 124.785 6.560 ;
        RECT 120.115 5.390 121.130 5.510 ;
        RECT 119.645 4.220 119.875 5.205 ;
        RECT 120.115 4.990 120.360 5.390 ;
        RECT 120.760 4.990 121.130 5.390 ;
        RECT 120.115 4.865 121.130 4.990 ;
        RECT 121.910 4.220 122.250 5.910 ;
        RECT 123.290 5.690 124.230 6.070 ;
        RECT 124.555 5.370 124.785 6.330 ;
        RECT 125.125 6.515 125.355 7.030 ;
        RECT 125.790 6.750 126.130 7.540 ;
        RECT 126.485 7.080 129.035 7.310 ;
        RECT 130.430 7.255 130.770 7.540 ;
        RECT 126.485 6.515 126.715 7.080 ;
        RECT 125.125 6.285 126.715 6.515 ;
        RECT 126.485 5.750 126.715 6.285 ;
        RECT 122.985 5.140 124.785 5.370 ;
        RECT 122.985 4.685 123.215 5.140 ;
        RECT 123.950 4.220 124.290 4.910 ;
        RECT 124.555 4.860 124.785 5.140 ;
        RECT 125.025 5.515 126.715 5.750 ;
        RECT 125.025 5.130 125.255 5.515 ;
        RECT 125.485 4.955 126.760 5.190 ;
        RECT 127.210 5.130 127.615 6.630 ;
        RECT 127.965 5.600 128.310 6.850 ;
        RECT 128.805 6.060 129.035 7.080 ;
        RECT 131.770 6.520 132.110 6.980 ;
        RECT 129.770 6.290 132.110 6.520 ;
        RECT 128.805 5.830 131.510 6.060 ;
        RECT 127.965 5.370 131.050 5.600 ;
        RECT 125.485 4.860 125.715 4.955 ;
        RECT 124.555 4.625 125.715 4.860 ;
        RECT 126.530 4.680 126.760 4.955 ;
        RECT 128.250 4.910 128.590 5.370 ;
        RECT 125.945 4.220 126.175 4.655 ;
        RECT 126.530 4.450 129.230 4.680 ;
        RECT 130.270 4.220 130.610 5.140 ;
        RECT 131.280 4.680 131.510 5.830 ;
        RECT 131.765 4.910 132.110 6.290 ;
        RECT 132.360 4.680 132.590 6.615 ;
        RECT 132.890 5.945 133.230 6.980 ;
        RECT 135.125 6.735 135.355 7.540 ;
        RECT 136.245 6.440 136.510 7.085 ;
        RECT 137.065 6.950 137.295 7.540 ;
        RECT 134.410 6.340 136.510 6.440 ;
        RECT 134.410 6.210 137.735 6.340 ;
        RECT 136.285 6.000 137.735 6.210 ;
        RECT 132.890 5.710 135.990 5.945 ;
        RECT 132.890 4.910 133.230 5.710 ;
        RECT 131.280 4.450 133.970 4.680 ;
        RECT 135.265 4.220 135.495 5.205 ;
        RECT 136.285 4.810 136.515 6.000 ;
        RECT 138.110 5.510 138.490 7.290 ;
        RECT 139.270 6.655 139.610 7.540 ;
        RECT 140.245 6.560 140.475 7.030 ;
        RECT 141.310 6.790 141.650 7.540 ;
        RECT 140.245 6.330 142.145 6.560 ;
        RECT 137.475 5.390 138.490 5.510 ;
        RECT 137.005 4.220 137.235 5.205 ;
        RECT 137.475 4.990 137.720 5.390 ;
        RECT 138.120 4.990 138.490 5.390 ;
        RECT 137.475 4.865 138.490 4.990 ;
        RECT 139.270 4.220 139.610 5.910 ;
        RECT 140.650 5.690 141.590 6.070 ;
        RECT 141.915 5.370 142.145 6.330 ;
        RECT 142.485 6.515 142.715 7.030 ;
        RECT 143.150 6.750 143.490 7.540 ;
        RECT 143.845 7.080 146.395 7.310 ;
        RECT 147.790 7.255 148.130 7.540 ;
        RECT 143.845 6.515 144.075 7.080 ;
        RECT 142.485 6.285 144.075 6.515 ;
        RECT 143.845 5.750 144.075 6.285 ;
        RECT 140.345 5.140 142.145 5.370 ;
        RECT 140.345 4.685 140.575 5.140 ;
        RECT 141.310 4.220 141.650 4.910 ;
        RECT 141.915 4.860 142.145 5.140 ;
        RECT 142.385 5.515 144.075 5.750 ;
        RECT 142.385 5.130 142.615 5.515 ;
        RECT 142.845 4.955 144.120 5.190 ;
        RECT 144.570 5.130 144.975 6.630 ;
        RECT 145.325 5.600 145.670 6.850 ;
        RECT 146.165 6.060 146.395 7.080 ;
        RECT 149.130 6.520 149.470 6.980 ;
        RECT 147.130 6.290 149.470 6.520 ;
        RECT 146.165 5.830 148.870 6.060 ;
        RECT 145.325 5.370 148.410 5.600 ;
        RECT 142.845 4.860 143.075 4.955 ;
        RECT 141.915 4.625 143.075 4.860 ;
        RECT 143.890 4.680 144.120 4.955 ;
        RECT 145.610 4.910 145.950 5.370 ;
        RECT 143.305 4.220 143.535 4.655 ;
        RECT 143.890 4.450 146.590 4.680 ;
        RECT 147.630 4.220 147.970 5.140 ;
        RECT 148.640 4.680 148.870 5.830 ;
        RECT 149.125 4.910 149.470 6.290 ;
        RECT 149.720 4.680 149.950 6.615 ;
        RECT 150.250 5.945 150.590 6.980 ;
        RECT 152.485 6.735 152.715 7.540 ;
        RECT 153.605 6.440 153.870 7.085 ;
        RECT 154.425 6.950 154.655 7.540 ;
        RECT 151.770 6.340 153.870 6.440 ;
        RECT 151.770 6.210 155.095 6.340 ;
        RECT 153.645 6.000 155.095 6.210 ;
        RECT 150.250 5.710 153.350 5.945 ;
        RECT 150.250 4.910 150.590 5.710 ;
        RECT 148.640 4.450 151.330 4.680 ;
        RECT 152.625 4.220 152.855 5.205 ;
        RECT 153.645 4.810 153.875 6.000 ;
        RECT 155.470 5.510 155.850 7.290 ;
        RECT 156.630 6.655 156.970 7.540 ;
        RECT 157.730 6.650 158.070 7.540 ;
        RECT 154.835 5.390 155.850 5.510 ;
        RECT 154.365 4.220 154.595 5.205 ;
        RECT 154.835 4.990 155.080 5.390 ;
        RECT 155.480 4.990 155.850 5.390 ;
        RECT 154.835 4.865 155.850 4.990 ;
        RECT 156.630 4.220 156.970 5.910 ;
        RECT 157.730 4.220 158.070 5.920 ;
        RECT 0.000 3.620 158.480 4.220 ;
        RECT 0.370 1.920 0.710 3.620 ;
        RECT 1.365 2.255 1.595 2.825 ;
        RECT 2.330 2.540 2.670 3.620 ;
        RECT 1.365 2.025 3.255 2.255 ;
        RECT 0.370 0.300 0.710 1.190 ;
        RECT 1.365 0.640 1.595 2.025 ;
        RECT 3.505 1.725 3.735 2.825 ;
        RECT 4.225 2.280 4.455 2.710 ;
        RECT 5.765 2.530 5.995 3.620 ;
        RECT 4.225 2.050 6.335 2.280 ;
        RECT 1.825 1.570 2.965 1.610 ;
        RECT 1.825 1.250 1.900 1.570 ;
        RECT 2.300 1.250 2.965 1.570 ;
        RECT 1.825 1.210 2.965 1.250 ;
        RECT 3.505 1.495 5.300 1.725 ;
        RECT 2.485 0.300 2.715 0.980 ;
        RECT 3.505 0.640 3.835 1.495 ;
        RECT 6.105 1.180 6.335 2.050 ;
        RECT 6.770 1.650 7.140 3.380 ;
        RECT 7.670 1.930 8.010 3.620 ;
        RECT 8.790 1.930 9.130 3.620 ;
        RECT 9.910 1.930 10.250 3.620 ;
        RECT 11.030 1.930 11.370 3.620 ;
        RECT 12.150 1.930 12.490 3.620 ;
        RECT 13.270 1.930 13.610 3.620 ;
        RECT 14.390 1.930 14.730 3.620 ;
        RECT 15.510 1.930 15.850 3.620 ;
        RECT 16.630 1.930 16.970 3.620 ;
        RECT 17.750 1.930 18.090 3.620 ;
        RECT 18.725 2.255 18.955 2.825 ;
        RECT 19.690 2.540 20.030 3.620 ;
        RECT 18.725 2.025 20.615 2.255 ;
        RECT 4.990 0.950 6.335 1.180 ;
        RECT 6.745 1.150 7.165 1.650 ;
        RECT 4.990 0.765 5.225 0.950 ;
        RECT 4.265 0.530 5.225 0.765 ;
        RECT 5.665 0.300 5.895 0.690 ;
        RECT 6.770 0.550 7.140 1.150 ;
        RECT 7.670 0.300 8.010 1.185 ;
        RECT 8.790 0.300 9.130 1.185 ;
        RECT 9.910 0.300 10.250 1.185 ;
        RECT 11.030 0.300 11.370 1.185 ;
        RECT 12.150 0.300 12.490 1.185 ;
        RECT 13.270 0.300 13.610 1.185 ;
        RECT 14.390 0.300 14.730 1.185 ;
        RECT 15.510 0.300 15.850 1.185 ;
        RECT 16.630 0.300 16.970 1.185 ;
        RECT 17.750 0.300 18.090 1.185 ;
        RECT 18.725 0.640 18.955 2.025 ;
        RECT 20.865 1.725 21.095 2.825 ;
        RECT 21.585 2.280 21.815 2.710 ;
        RECT 23.125 2.530 23.355 3.620 ;
        RECT 21.585 2.050 23.695 2.280 ;
        RECT 19.185 1.210 20.325 1.610 ;
        RECT 20.865 1.495 22.660 1.725 ;
        RECT 19.845 0.300 20.075 0.980 ;
        RECT 20.865 0.640 21.195 1.495 ;
        RECT 23.465 1.180 23.695 2.050 ;
        RECT 24.130 1.650 24.500 3.380 ;
        RECT 25.030 1.930 25.370 3.620 ;
        RECT 26.150 1.930 26.490 3.620 ;
        RECT 27.270 1.930 27.610 3.620 ;
        RECT 28.390 1.930 28.730 3.620 ;
        RECT 29.510 1.930 29.850 3.620 ;
        RECT 30.630 1.930 30.970 3.620 ;
        RECT 31.750 1.930 32.090 3.620 ;
        RECT 32.870 1.930 33.210 3.620 ;
        RECT 33.990 1.930 34.330 3.620 ;
        RECT 35.110 1.930 35.450 3.620 ;
        RECT 36.085 2.255 36.315 2.825 ;
        RECT 37.050 2.540 37.390 3.620 ;
        RECT 36.085 2.025 37.975 2.255 ;
        RECT 22.350 0.950 23.695 1.180 ;
        RECT 24.105 1.150 24.525 1.650 ;
        RECT 22.350 0.765 22.585 0.950 ;
        RECT 21.625 0.530 22.585 0.765 ;
        RECT 23.025 0.300 23.255 0.690 ;
        RECT 24.130 0.550 24.500 1.150 ;
        RECT 25.030 0.300 25.370 1.185 ;
        RECT 26.150 0.300 26.490 1.185 ;
        RECT 27.270 0.300 27.610 1.185 ;
        RECT 28.390 0.300 28.730 1.185 ;
        RECT 29.510 0.300 29.850 1.185 ;
        RECT 30.630 0.300 30.970 1.185 ;
        RECT 31.750 0.300 32.090 1.185 ;
        RECT 32.870 0.300 33.210 1.185 ;
        RECT 33.990 0.300 34.330 1.185 ;
        RECT 35.110 0.300 35.450 1.185 ;
        RECT 36.085 0.640 36.315 2.025 ;
        RECT 38.225 1.725 38.455 2.825 ;
        RECT 38.945 2.280 39.175 2.710 ;
        RECT 40.485 2.530 40.715 3.620 ;
        RECT 38.945 2.050 41.055 2.280 ;
        RECT 36.545 1.210 37.685 1.610 ;
        RECT 38.225 1.495 40.020 1.725 ;
        RECT 37.205 0.300 37.435 0.980 ;
        RECT 38.225 0.640 38.555 1.495 ;
        RECT 40.825 1.180 41.055 2.050 ;
        RECT 41.490 1.650 41.860 3.380 ;
        RECT 42.390 1.930 42.730 3.620 ;
        RECT 43.510 1.930 43.850 3.620 ;
        RECT 44.630 1.930 44.970 3.620 ;
        RECT 45.750 1.930 46.090 3.620 ;
        RECT 46.870 1.930 47.210 3.620 ;
        RECT 47.990 1.930 48.330 3.620 ;
        RECT 49.110 1.930 49.450 3.620 ;
        RECT 50.230 1.930 50.570 3.620 ;
        RECT 51.350 1.930 51.690 3.620 ;
        RECT 52.470 1.930 52.810 3.620 ;
        RECT 53.445 2.255 53.675 2.825 ;
        RECT 54.410 2.540 54.750 3.620 ;
        RECT 53.445 2.025 55.335 2.255 ;
        RECT 39.710 0.950 41.055 1.180 ;
        RECT 41.465 1.150 41.885 1.650 ;
        RECT 39.710 0.765 39.945 0.950 ;
        RECT 38.985 0.530 39.945 0.765 ;
        RECT 40.385 0.300 40.615 0.690 ;
        RECT 41.490 0.550 41.860 1.150 ;
        RECT 42.390 0.300 42.730 1.185 ;
        RECT 43.510 0.300 43.850 1.185 ;
        RECT 44.630 0.300 44.970 1.185 ;
        RECT 45.750 0.300 46.090 1.185 ;
        RECT 46.870 0.300 47.210 1.185 ;
        RECT 47.990 0.300 48.330 1.185 ;
        RECT 49.110 0.300 49.450 1.185 ;
        RECT 50.230 0.300 50.570 1.185 ;
        RECT 51.350 0.300 51.690 1.185 ;
        RECT 52.470 0.300 52.810 1.185 ;
        RECT 53.445 0.640 53.675 2.025 ;
        RECT 55.585 1.725 55.815 2.825 ;
        RECT 56.305 2.280 56.535 2.710 ;
        RECT 57.845 2.530 58.075 3.620 ;
        RECT 56.305 2.050 58.415 2.280 ;
        RECT 53.905 1.210 55.045 1.610 ;
        RECT 55.585 1.495 57.380 1.725 ;
        RECT 54.565 0.300 54.795 0.980 ;
        RECT 55.585 0.640 55.915 1.495 ;
        RECT 58.185 1.180 58.415 2.050 ;
        RECT 58.850 1.650 59.220 3.380 ;
        RECT 59.750 1.930 60.090 3.620 ;
        RECT 60.870 1.930 61.210 3.620 ;
        RECT 61.990 1.930 62.330 3.620 ;
        RECT 63.110 1.930 63.450 3.620 ;
        RECT 64.230 1.930 64.570 3.620 ;
        RECT 65.350 1.930 65.690 3.620 ;
        RECT 66.470 1.930 66.810 3.620 ;
        RECT 67.590 1.930 67.930 3.620 ;
        RECT 68.710 1.930 69.050 3.620 ;
        RECT 69.830 1.930 70.170 3.620 ;
        RECT 70.805 2.255 71.035 2.825 ;
        RECT 71.770 2.540 72.110 3.620 ;
        RECT 70.805 2.025 72.695 2.255 ;
        RECT 57.070 0.950 58.415 1.180 ;
        RECT 58.825 1.150 59.245 1.650 ;
        RECT 57.070 0.765 57.305 0.950 ;
        RECT 56.345 0.530 57.305 0.765 ;
        RECT 57.745 0.300 57.975 0.690 ;
        RECT 58.850 0.550 59.220 1.150 ;
        RECT 59.750 0.300 60.090 1.185 ;
        RECT 60.870 0.300 61.210 1.185 ;
        RECT 61.990 0.300 62.330 1.185 ;
        RECT 63.110 0.300 63.450 1.185 ;
        RECT 64.230 0.300 64.570 1.185 ;
        RECT 65.350 0.300 65.690 1.185 ;
        RECT 66.470 0.300 66.810 1.185 ;
        RECT 67.590 0.300 67.930 1.185 ;
        RECT 68.710 0.300 69.050 1.185 ;
        RECT 69.830 0.300 70.170 1.185 ;
        RECT 70.805 0.640 71.035 2.025 ;
        RECT 72.945 1.725 73.175 2.825 ;
        RECT 73.665 2.280 73.895 2.710 ;
        RECT 75.205 2.530 75.435 3.620 ;
        RECT 73.665 2.050 75.775 2.280 ;
        RECT 71.265 1.210 72.405 1.610 ;
        RECT 72.945 1.495 74.740 1.725 ;
        RECT 71.925 0.300 72.155 0.980 ;
        RECT 72.945 0.640 73.275 1.495 ;
        RECT 75.545 1.180 75.775 2.050 ;
        RECT 76.210 1.650 76.580 3.380 ;
        RECT 77.110 1.930 77.450 3.620 ;
        RECT 78.230 1.930 78.570 3.620 ;
        RECT 79.350 1.930 79.690 3.620 ;
        RECT 80.470 1.930 80.810 3.620 ;
        RECT 81.590 1.930 81.930 3.620 ;
        RECT 82.710 1.930 83.050 3.620 ;
        RECT 83.830 1.930 84.170 3.620 ;
        RECT 84.950 1.930 85.290 3.620 ;
        RECT 86.070 1.930 86.410 3.620 ;
        RECT 87.190 1.930 87.530 3.620 ;
        RECT 88.165 2.255 88.395 2.825 ;
        RECT 89.130 2.540 89.470 3.620 ;
        RECT 88.165 2.025 90.055 2.255 ;
        RECT 74.430 0.950 75.775 1.180 ;
        RECT 76.185 1.150 76.605 1.650 ;
        RECT 74.430 0.765 74.665 0.950 ;
        RECT 73.705 0.530 74.665 0.765 ;
        RECT 75.105 0.300 75.335 0.690 ;
        RECT 76.210 0.550 76.580 1.150 ;
        RECT 77.110 0.300 77.450 1.185 ;
        RECT 78.230 0.300 78.570 1.185 ;
        RECT 79.350 0.300 79.690 1.185 ;
        RECT 80.470 0.300 80.810 1.185 ;
        RECT 81.590 0.300 81.930 1.185 ;
        RECT 82.710 0.300 83.050 1.185 ;
        RECT 83.830 0.300 84.170 1.185 ;
        RECT 84.950 0.300 85.290 1.185 ;
        RECT 86.070 0.300 86.410 1.185 ;
        RECT 87.190 0.300 87.530 1.185 ;
        RECT 88.165 0.640 88.395 2.025 ;
        RECT 90.305 1.725 90.535 2.825 ;
        RECT 91.025 2.280 91.255 2.710 ;
        RECT 92.565 2.530 92.795 3.620 ;
        RECT 91.025 2.050 93.135 2.280 ;
        RECT 88.625 1.210 89.765 1.610 ;
        RECT 90.305 1.495 92.100 1.725 ;
        RECT 89.285 0.300 89.515 0.980 ;
        RECT 90.305 0.640 90.635 1.495 ;
        RECT 92.905 1.180 93.135 2.050 ;
        RECT 93.570 1.650 93.940 3.380 ;
        RECT 94.470 1.930 94.810 3.620 ;
        RECT 95.590 1.930 95.930 3.620 ;
        RECT 96.710 1.930 97.050 3.620 ;
        RECT 97.830 1.930 98.170 3.620 ;
        RECT 98.950 1.930 99.290 3.620 ;
        RECT 100.070 1.930 100.410 3.620 ;
        RECT 101.190 1.930 101.530 3.620 ;
        RECT 102.310 1.930 102.650 3.620 ;
        RECT 103.430 1.930 103.770 3.620 ;
        RECT 104.550 1.930 104.890 3.620 ;
        RECT 105.525 2.255 105.755 2.825 ;
        RECT 106.490 2.540 106.830 3.620 ;
        RECT 105.525 2.025 107.415 2.255 ;
        RECT 91.790 0.950 93.135 1.180 ;
        RECT 93.545 1.150 93.965 1.650 ;
        RECT 91.790 0.765 92.025 0.950 ;
        RECT 91.065 0.530 92.025 0.765 ;
        RECT 92.465 0.300 92.695 0.690 ;
        RECT 93.570 0.550 93.940 1.150 ;
        RECT 94.470 0.300 94.810 1.185 ;
        RECT 95.590 0.300 95.930 1.185 ;
        RECT 96.710 0.300 97.050 1.185 ;
        RECT 97.830 0.300 98.170 1.185 ;
        RECT 98.950 0.300 99.290 1.185 ;
        RECT 100.070 0.300 100.410 1.185 ;
        RECT 101.190 0.300 101.530 1.185 ;
        RECT 102.310 0.300 102.650 1.185 ;
        RECT 103.430 0.300 103.770 1.185 ;
        RECT 104.550 0.300 104.890 1.185 ;
        RECT 105.525 0.640 105.755 2.025 ;
        RECT 107.665 1.725 107.895 2.825 ;
        RECT 108.385 2.280 108.615 2.710 ;
        RECT 109.925 2.530 110.155 3.620 ;
        RECT 108.385 2.050 110.495 2.280 ;
        RECT 105.985 1.210 107.125 1.610 ;
        RECT 107.665 1.495 109.460 1.725 ;
        RECT 106.645 0.300 106.875 0.980 ;
        RECT 107.665 0.640 107.995 1.495 ;
        RECT 110.265 1.180 110.495 2.050 ;
        RECT 110.930 1.650 111.300 3.380 ;
        RECT 111.830 1.930 112.170 3.620 ;
        RECT 112.950 1.930 113.290 3.620 ;
        RECT 114.070 1.930 114.410 3.620 ;
        RECT 115.190 1.930 115.530 3.620 ;
        RECT 116.310 1.930 116.650 3.620 ;
        RECT 117.430 1.930 117.770 3.620 ;
        RECT 118.550 1.930 118.890 3.620 ;
        RECT 119.670 1.930 120.010 3.620 ;
        RECT 120.790 1.930 121.130 3.620 ;
        RECT 121.910 1.930 122.250 3.620 ;
        RECT 122.885 2.255 123.115 2.825 ;
        RECT 123.850 2.540 124.190 3.620 ;
        RECT 122.885 2.025 124.775 2.255 ;
        RECT 109.150 0.950 110.495 1.180 ;
        RECT 110.905 1.150 111.325 1.650 ;
        RECT 109.150 0.765 109.385 0.950 ;
        RECT 108.425 0.530 109.385 0.765 ;
        RECT 109.825 0.300 110.055 0.690 ;
        RECT 110.930 0.550 111.300 1.150 ;
        RECT 111.830 0.300 112.170 1.185 ;
        RECT 112.950 0.300 113.290 1.185 ;
        RECT 114.070 0.300 114.410 1.185 ;
        RECT 115.190 0.300 115.530 1.185 ;
        RECT 116.310 0.300 116.650 1.185 ;
        RECT 117.430 0.300 117.770 1.185 ;
        RECT 118.550 0.300 118.890 1.185 ;
        RECT 119.670 0.300 120.010 1.185 ;
        RECT 120.790 0.300 121.130 1.185 ;
        RECT 121.910 0.300 122.250 1.185 ;
        RECT 122.885 0.640 123.115 2.025 ;
        RECT 125.025 1.725 125.255 2.825 ;
        RECT 125.745 2.280 125.975 2.710 ;
        RECT 127.285 2.530 127.515 3.620 ;
        RECT 125.745 2.050 127.855 2.280 ;
        RECT 123.345 1.210 124.485 1.610 ;
        RECT 125.025 1.495 126.820 1.725 ;
        RECT 124.005 0.300 124.235 0.980 ;
        RECT 125.025 0.640 125.355 1.495 ;
        RECT 127.625 1.180 127.855 2.050 ;
        RECT 128.290 1.650 128.660 3.380 ;
        RECT 129.190 1.930 129.530 3.620 ;
        RECT 130.310 1.930 130.650 3.620 ;
        RECT 131.430 1.930 131.770 3.620 ;
        RECT 132.550 1.930 132.890 3.620 ;
        RECT 133.670 1.930 134.010 3.620 ;
        RECT 134.790 1.930 135.130 3.620 ;
        RECT 135.910 1.930 136.250 3.620 ;
        RECT 137.030 1.930 137.370 3.620 ;
        RECT 138.150 1.930 138.490 3.620 ;
        RECT 139.270 1.930 139.610 3.620 ;
        RECT 140.245 2.255 140.475 2.825 ;
        RECT 141.210 2.540 141.550 3.620 ;
        RECT 140.245 2.025 142.135 2.255 ;
        RECT 126.510 0.950 127.855 1.180 ;
        RECT 128.265 1.150 128.685 1.650 ;
        RECT 126.510 0.765 126.745 0.950 ;
        RECT 125.785 0.530 126.745 0.765 ;
        RECT 127.185 0.300 127.415 0.690 ;
        RECT 128.290 0.550 128.660 1.150 ;
        RECT 129.190 0.300 129.530 1.185 ;
        RECT 130.310 0.300 130.650 1.185 ;
        RECT 131.430 0.300 131.770 1.185 ;
        RECT 132.550 0.300 132.890 1.185 ;
        RECT 133.670 0.300 134.010 1.185 ;
        RECT 134.790 0.300 135.130 1.185 ;
        RECT 135.910 0.300 136.250 1.185 ;
        RECT 137.030 0.300 137.370 1.185 ;
        RECT 138.150 0.300 138.490 1.185 ;
        RECT 139.270 0.300 139.610 1.185 ;
        RECT 140.245 0.640 140.475 2.025 ;
        RECT 142.385 1.725 142.615 2.825 ;
        RECT 143.105 2.280 143.335 2.710 ;
        RECT 144.645 2.530 144.875 3.620 ;
        RECT 143.105 2.050 145.215 2.280 ;
        RECT 140.705 1.210 141.845 1.610 ;
        RECT 142.385 1.495 144.180 1.725 ;
        RECT 141.365 0.300 141.595 0.980 ;
        RECT 142.385 0.640 142.715 1.495 ;
        RECT 144.985 1.180 145.215 2.050 ;
        RECT 145.650 1.650 146.020 3.380 ;
        RECT 146.550 1.930 146.890 3.620 ;
        RECT 147.670 1.930 148.010 3.620 ;
        RECT 148.790 1.930 149.130 3.620 ;
        RECT 149.910 1.930 150.250 3.620 ;
        RECT 151.030 1.930 151.370 3.620 ;
        RECT 152.150 1.930 152.490 3.620 ;
        RECT 153.270 1.930 153.610 3.620 ;
        RECT 154.390 1.930 154.730 3.620 ;
        RECT 155.510 1.930 155.850 3.620 ;
        RECT 156.630 1.930 156.970 3.620 ;
        RECT 157.730 1.920 158.070 3.620 ;
        RECT 143.870 0.950 145.215 1.180 ;
        RECT 145.625 1.150 146.045 1.650 ;
        RECT 143.870 0.765 144.105 0.950 ;
        RECT 143.145 0.530 144.105 0.765 ;
        RECT 144.545 0.300 144.775 0.690 ;
        RECT 145.650 0.550 146.020 1.150 ;
        RECT 146.550 0.300 146.890 1.185 ;
        RECT 147.670 0.300 148.010 1.185 ;
        RECT 148.790 0.300 149.130 1.185 ;
        RECT 149.910 0.300 150.250 1.185 ;
        RECT 151.030 0.300 151.370 1.185 ;
        RECT 152.150 0.300 152.490 1.185 ;
        RECT 153.270 0.300 153.610 1.185 ;
        RECT 154.390 0.300 154.730 1.185 ;
        RECT 155.510 0.300 155.850 1.185 ;
        RECT 156.630 0.300 156.970 1.185 ;
        RECT 157.730 0.300 158.070 1.190 ;
        RECT 0.000 -0.300 158.480 0.300 ;
      LAYER Metal2 ;
        RECT 2.740 9.030 3.280 9.450 ;
        RECT 8.955 9.030 20.640 9.450 ;
        RECT 26.315 9.030 38.000 9.450 ;
        RECT 43.675 9.030 55.360 9.450 ;
        RECT 61.035 9.030 72.720 9.450 ;
        RECT 78.395 9.030 90.080 9.450 ;
        RECT 95.755 9.030 107.440 9.450 ;
        RECT 113.115 9.030 124.800 9.450 ;
        RECT 130.475 9.030 142.160 9.450 ;
        RECT 147.835 9.030 148.375 9.450 ;
        RECT 0.300 -0.270 0.720 8.110 ;
        RECT 9.015 6.820 9.435 9.030 ;
        RECT 26.375 6.820 26.795 9.030 ;
        RECT 43.735 6.820 44.155 9.030 ;
        RECT 61.095 6.820 61.515 9.030 ;
        RECT 78.455 6.820 78.875 9.030 ;
        RECT 95.815 6.820 96.235 9.030 ;
        RECT 113.175 6.820 113.595 9.030 ;
        RECT 130.535 6.820 130.955 9.030 ;
        RECT 147.895 6.820 148.315 9.030 ;
        RECT 1.980 6.400 9.435 6.820 ;
        RECT 19.340 6.400 26.795 6.820 ;
        RECT 36.700 6.400 44.155 6.820 ;
        RECT 54.060 6.400 61.515 6.820 ;
        RECT 71.420 6.400 78.875 6.820 ;
        RECT 88.780 6.400 96.235 6.820 ;
        RECT 106.140 6.400 113.595 6.820 ;
        RECT 123.500 6.400 130.955 6.820 ;
        RECT 140.860 6.400 148.315 6.820 ;
        RECT 1.980 5.610 2.400 6.400 ;
        RECT 5.620 5.230 7.165 5.650 ;
        RECT 19.340 5.610 19.760 6.400 ;
        RECT 22.980 5.230 24.525 5.650 ;
        RECT 36.700 5.610 37.120 6.400 ;
        RECT 40.340 5.230 41.885 5.650 ;
        RECT 54.060 5.610 54.480 6.400 ;
        RECT 57.700 5.230 59.245 5.650 ;
        RECT 71.420 5.610 71.840 6.400 ;
        RECT 75.060 5.230 76.605 5.650 ;
        RECT 88.780 5.610 89.200 6.400 ;
        RECT 92.420 5.230 93.965 5.650 ;
        RECT 106.140 5.610 106.560 6.400 ;
        RECT 109.780 5.230 111.325 5.650 ;
        RECT 123.500 5.610 123.920 6.400 ;
        RECT 127.140 5.230 128.685 5.650 ;
        RECT 140.860 5.610 141.280 6.400 ;
        RECT 144.500 5.230 146.045 5.650 ;
        RECT 6.745 1.610 7.165 5.230 ;
        RECT 24.105 1.610 24.525 5.230 ;
        RECT 41.465 1.610 41.885 5.230 ;
        RECT 58.825 1.610 59.245 5.230 ;
        RECT 76.185 1.610 76.605 5.230 ;
        RECT 93.545 1.610 93.965 5.230 ;
        RECT 110.905 1.610 111.325 5.230 ;
        RECT 128.265 1.610 128.685 5.230 ;
        RECT 145.625 1.610 146.045 5.230 ;
        RECT 157.660 3.650 158.080 12.030 ;
        RECT 2.440 1.190 2.980 1.610 ;
        RECT 6.685 1.190 20.340 1.610 ;
        RECT 24.045 1.190 37.700 1.610 ;
        RECT 41.405 1.190 55.060 1.610 ;
        RECT 58.765 1.190 72.420 1.610 ;
        RECT 76.125 1.190 89.780 1.610 ;
        RECT 93.485 1.190 107.140 1.610 ;
        RECT 110.845 1.190 124.500 1.610 ;
        RECT 128.205 1.190 141.860 1.610 ;
        RECT 145.565 1.190 146.105 1.610 ;
  END
END fine_line
END LIBRARY

